# Generated by FakeRAM 2.0
VERSION 5.7 ;
BUSBITCHARS "[]" ;
PROPERTYDEFINITIONS
  MACRO width INTEGER ;
  MACRO depth INTEGER ;
  MACRO banks INTEGER ;
END PROPERTYDEFINITIONS
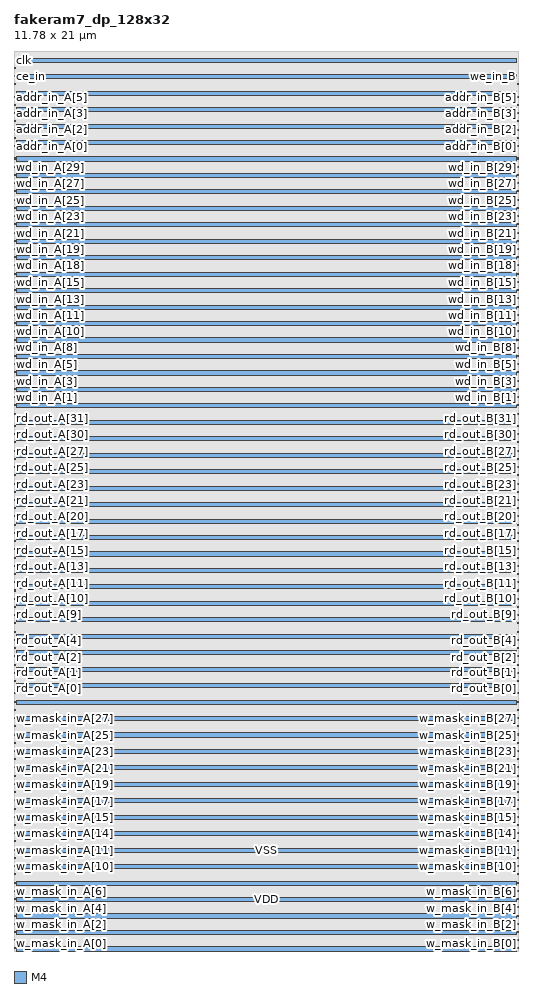
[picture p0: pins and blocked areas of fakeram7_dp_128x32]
MACRO fakeram7_dp_128x32
  PROPERTY width 32 ;
  PROPERTY depth 128 ;
  PROPERTY banks 2 ;
  FOREIGN fakeram7_dp_128x32 0 0 ;
  SYMMETRY X Y ;
  SIZE 11.780 BY 21.000 ;
  CLASS BLOCK ;
  PIN w_mask_in_A[0]
    DIRECTION INPUT ;
    USE SIGNAL ;
    SHAPE ABUTMENT ;
    PORT
      LAYER M4 ;
      RECT 0.000 0.048 0.024 0.072 ;
    END
  END w_mask_in_A[0]
  PIN w_mask_in_B[0]
    DIRECTION INPUT ;
    USE SIGNAL ;
    SHAPE ABUTMENT ;
    PORT
      LAYER M4 ;
      RECT 11.756 0.048 11.780 0.072 ;
    END
  END w_mask_in_B[0]
  PIN w_mask_in_A[1]
    DIRECTION INPUT ;
    USE SIGNAL ;
    SHAPE ABUTMENT ;
    PORT
      LAYER M4 ;
      RECT 0.000 0.240 0.024 0.264 ;
    END
  END w_mask_in_A[1]
  PIN w_mask_in_B[1]
    DIRECTION INPUT ;
    USE SIGNAL ;
    SHAPE ABUTMENT ;
    PORT
      LAYER M4 ;
      RECT 11.756 0.240 11.780 0.264 ;
    END
  END w_mask_in_B[1]
  PIN w_mask_in_A[2]
    DIRECTION INPUT ;
    USE SIGNAL ;
    SHAPE ABUTMENT ;
    PORT
      LAYER M4 ;
      RECT 0.000 0.432 0.024 0.456 ;
    END
  END w_mask_in_A[2]
  PIN w_mask_in_B[2]
    DIRECTION INPUT ;
    USE SIGNAL ;
    SHAPE ABUTMENT ;
    PORT
      LAYER M4 ;
      RECT 11.756 0.432 11.780 0.456 ;
    END
  END w_mask_in_B[2]
  PIN w_mask_in_A[3]
    DIRECTION INPUT ;
    USE SIGNAL ;
    SHAPE ABUTMENT ;
    PORT
      LAYER M4 ;
      RECT 0.000 0.624 0.024 0.648 ;
    END
  END w_mask_in_A[3]
  PIN w_mask_in_B[3]
    DIRECTION INPUT ;
    USE SIGNAL ;
    SHAPE ABUTMENT ;
    PORT
      LAYER M4 ;
      RECT 11.756 0.624 11.780 0.648 ;
    END
  END w_mask_in_B[3]
  PIN w_mask_in_A[4]
    DIRECTION INPUT ;
    USE SIGNAL ;
    SHAPE ABUTMENT ;
    PORT
      LAYER M4 ;
      RECT 0.000 0.816 0.024 0.840 ;
    END
  END w_mask_in_A[4]
  PIN w_mask_in_B[4]
    DIRECTION INPUT ;
    USE SIGNAL ;
    SHAPE ABUTMENT ;
    PORT
      LAYER M4 ;
      RECT 11.756 0.816 11.780 0.840 ;
    END
  END w_mask_in_B[4]
  PIN w_mask_in_A[5]
    DIRECTION INPUT ;
    USE SIGNAL ;
    SHAPE ABUTMENT ;
    PORT
      LAYER M4 ;
      RECT 0.000 1.008 0.024 1.032 ;
    END
  END w_mask_in_A[5]
  PIN w_mask_in_B[5]
    DIRECTION INPUT ;
    USE SIGNAL ;
    SHAPE ABUTMENT ;
    PORT
      LAYER M4 ;
      RECT 11.756 1.008 11.780 1.032 ;
    END
  END w_mask_in_B[5]
  PIN w_mask_in_A[6]
    DIRECTION INPUT ;
    USE SIGNAL ;
    SHAPE ABUTMENT ;
    PORT
      LAYER M4 ;
      RECT 0.000 1.200 0.024 1.224 ;
    END
  END w_mask_in_A[6]
  PIN w_mask_in_B[6]
    DIRECTION INPUT ;
    USE SIGNAL ;
    SHAPE ABUTMENT ;
    PORT
      LAYER M4 ;
      RECT 11.756 1.200 11.780 1.224 ;
    END
  END w_mask_in_B[6]
  PIN w_mask_in_A[7]
    DIRECTION INPUT ;
    USE SIGNAL ;
    SHAPE ABUTMENT ;
    PORT
      LAYER M4 ;
      RECT 0.000 1.392 0.024 1.416 ;
    END
  END w_mask_in_A[7]
  PIN w_mask_in_B[7]
    DIRECTION INPUT ;
    USE SIGNAL ;
    SHAPE ABUTMENT ;
    PORT
      LAYER M4 ;
      RECT 11.756 1.392 11.780 1.416 ;
    END
  END w_mask_in_B[7]
  PIN w_mask_in_A[8]
    DIRECTION INPUT ;
    USE SIGNAL ;
    SHAPE ABUTMENT ;
    PORT
      LAYER M4 ;
      RECT 0.000 1.584 0.024 1.608 ;
    END
  END w_mask_in_A[8]
  PIN w_mask_in_B[8]
    DIRECTION INPUT ;
    USE SIGNAL ;
    SHAPE ABUTMENT ;
    PORT
      LAYER M4 ;
      RECT 11.756 1.584 11.780 1.608 ;
    END
  END w_mask_in_B[8]
  PIN w_mask_in_A[9]
    DIRECTION INPUT ;
    USE SIGNAL ;
    SHAPE ABUTMENT ;
    PORT
      LAYER M4 ;
      RECT 0.000 1.776 0.024 1.800 ;
    END
  END w_mask_in_A[9]
  PIN w_mask_in_B[9]
    DIRECTION INPUT ;
    USE SIGNAL ;
    SHAPE ABUTMENT ;
    PORT
      LAYER M4 ;
      RECT 11.756 1.776 11.780 1.800 ;
    END
  END w_mask_in_B[9]
  PIN w_mask_in_A[10]
    DIRECTION INPUT ;
    USE SIGNAL ;
    SHAPE ABUTMENT ;
    PORT
      LAYER M4 ;
      RECT 0.000 1.968 0.024 1.992 ;
    END
  END w_mask_in_A[10]
  PIN w_mask_in_B[10]
    DIRECTION INPUT ;
    USE SIGNAL ;
    SHAPE ABUTMENT ;
    PORT
      LAYER M4 ;
      RECT 11.756 1.968 11.780 1.992 ;
    END
  END w_mask_in_B[10]
  PIN w_mask_in_A[11]
    DIRECTION INPUT ;
    USE SIGNAL ;
    SHAPE ABUTMENT ;
    PORT
      LAYER M4 ;
      RECT 0.000 2.160 0.024 2.184 ;
    END
  END w_mask_in_A[11]
  PIN w_mask_in_B[11]
    DIRECTION INPUT ;
    USE SIGNAL ;
    SHAPE ABUTMENT ;
    PORT
      LAYER M4 ;
      RECT 11.756 2.160 11.780 2.184 ;
    END
  END w_mask_in_B[11]
  PIN w_mask_in_A[12]
    DIRECTION INPUT ;
    USE SIGNAL ;
    SHAPE ABUTMENT ;
    PORT
      LAYER M4 ;
      RECT 0.000 2.352 0.024 2.376 ;
    END
  END w_mask_in_A[12]
  PIN w_mask_in_B[12]
    DIRECTION INPUT ;
    USE SIGNAL ;
    SHAPE ABUTMENT ;
    PORT
      LAYER M4 ;
      RECT 11.756 2.352 11.780 2.376 ;
    END
  END w_mask_in_B[12]
  PIN w_mask_in_A[13]
    DIRECTION INPUT ;
    USE SIGNAL ;
    SHAPE ABUTMENT ;
    PORT
      LAYER M4 ;
      RECT 0.000 2.544 0.024 2.568 ;
    END
  END w_mask_in_A[13]
  PIN w_mask_in_B[13]
    DIRECTION INPUT ;
    USE SIGNAL ;
    SHAPE ABUTMENT ;
    PORT
      LAYER M4 ;
      RECT 11.756 2.544 11.780 2.568 ;
    END
  END w_mask_in_B[13]
  PIN w_mask_in_A[14]
    DIRECTION INPUT ;
    USE SIGNAL ;
    SHAPE ABUTMENT ;
    PORT
      LAYER M4 ;
      RECT 0.000 2.736 0.024 2.760 ;
    END
  END w_mask_in_A[14]
  PIN w_mask_in_B[14]
    DIRECTION INPUT ;
    USE SIGNAL ;
    SHAPE ABUTMENT ;
    PORT
      LAYER M4 ;
      RECT 11.756 2.736 11.780 2.760 ;
    END
  END w_mask_in_B[14]
  PIN w_mask_in_A[15]
    DIRECTION INPUT ;
    USE SIGNAL ;
    SHAPE ABUTMENT ;
    PORT
      LAYER M4 ;
      RECT 0.000 2.928 0.024 2.952 ;
    END
  END w_mask_in_A[15]
  PIN w_mask_in_B[15]
    DIRECTION INPUT ;
    USE SIGNAL ;
    SHAPE ABUTMENT ;
    PORT
      LAYER M4 ;
      RECT 11.756 2.928 11.780 2.952 ;
    END
  END w_mask_in_B[15]
  PIN w_mask_in_A[16]
    DIRECTION INPUT ;
    USE SIGNAL ;
    SHAPE ABUTMENT ;
    PORT
      LAYER M4 ;
      RECT 0.000 3.120 0.024 3.144 ;
    END
  END w_mask_in_A[16]
  PIN w_mask_in_B[16]
    DIRECTION INPUT ;
    USE SIGNAL ;
    SHAPE ABUTMENT ;
    PORT
      LAYER M4 ;
      RECT 11.756 3.120 11.780 3.144 ;
    END
  END w_mask_in_B[16]
  PIN w_mask_in_A[17]
    DIRECTION INPUT ;
    USE SIGNAL ;
    SHAPE ABUTMENT ;
    PORT
      LAYER M4 ;
      RECT 0.000 3.312 0.024 3.336 ;
    END
  END w_mask_in_A[17]
  PIN w_mask_in_B[17]
    DIRECTION INPUT ;
    USE SIGNAL ;
    SHAPE ABUTMENT ;
    PORT
      LAYER M4 ;
      RECT 11.756 3.312 11.780 3.336 ;
    END
  END w_mask_in_B[17]
  PIN w_mask_in_A[18]
    DIRECTION INPUT ;
    USE SIGNAL ;
    SHAPE ABUTMENT ;
    PORT
      LAYER M4 ;
      RECT 0.000 3.504 0.024 3.528 ;
    END
  END w_mask_in_A[18]
  PIN w_mask_in_B[18]
    DIRECTION INPUT ;
    USE SIGNAL ;
    SHAPE ABUTMENT ;
    PORT
      LAYER M4 ;
      RECT 11.756 3.504 11.780 3.528 ;
    END
  END w_mask_in_B[18]
  PIN w_mask_in_A[19]
    DIRECTION INPUT ;
    USE SIGNAL ;
    SHAPE ABUTMENT ;
    PORT
      LAYER M4 ;
      RECT 0.000 3.696 0.024 3.720 ;
    END
  END w_mask_in_A[19]
  PIN w_mask_in_B[19]
    DIRECTION INPUT ;
    USE SIGNAL ;
    SHAPE ABUTMENT ;
    PORT
      LAYER M4 ;
      RECT 11.756 3.696 11.780 3.720 ;
    END
  END w_mask_in_B[19]
  PIN w_mask_in_A[20]
    DIRECTION INPUT ;
    USE SIGNAL ;
    SHAPE ABUTMENT ;
    PORT
      LAYER M4 ;
      RECT 0.000 3.888 0.024 3.912 ;
    END
  END w_mask_in_A[20]
  PIN w_mask_in_B[20]
    DIRECTION INPUT ;
    USE SIGNAL ;
    SHAPE ABUTMENT ;
    PORT
      LAYER M4 ;
      RECT 11.756 3.888 11.780 3.912 ;
    END
  END w_mask_in_B[20]
  PIN w_mask_in_A[21]
    DIRECTION INPUT ;
    USE SIGNAL ;
    SHAPE ABUTMENT ;
    PORT
      LAYER M4 ;
      RECT 0.000 4.080 0.024 4.104 ;
    END
  END w_mask_in_A[21]
  PIN w_mask_in_B[21]
    DIRECTION INPUT ;
    USE SIGNAL ;
    SHAPE ABUTMENT ;
    PORT
      LAYER M4 ;
      RECT 11.756 4.080 11.780 4.104 ;
    END
  END w_mask_in_B[21]
  PIN w_mask_in_A[22]
    DIRECTION INPUT ;
    USE SIGNAL ;
    SHAPE ABUTMENT ;
    PORT
      LAYER M4 ;
      RECT 0.000 4.272 0.024 4.296 ;
    END
  END w_mask_in_A[22]
  PIN w_mask_in_B[22]
    DIRECTION INPUT ;
    USE SIGNAL ;
    SHAPE ABUTMENT ;
    PORT
      LAYER M4 ;
      RECT 11.756 4.272 11.780 4.296 ;
    END
  END w_mask_in_B[22]
  PIN w_mask_in_A[23]
    DIRECTION INPUT ;
    USE SIGNAL ;
    SHAPE ABUTMENT ;
    PORT
      LAYER M4 ;
      RECT 0.000 4.464 0.024 4.488 ;
    END
  END w_mask_in_A[23]
  PIN w_mask_in_B[23]
    DIRECTION INPUT ;
    USE SIGNAL ;
    SHAPE ABUTMENT ;
    PORT
      LAYER M4 ;
      RECT 11.756 4.464 11.780 4.488 ;
    END
  END w_mask_in_B[23]
  PIN w_mask_in_A[24]
    DIRECTION INPUT ;
    USE SIGNAL ;
    SHAPE ABUTMENT ;
    PORT
      LAYER M4 ;
      RECT 0.000 4.656 0.024 4.680 ;
    END
  END w_mask_in_A[24]
  PIN w_mask_in_B[24]
    DIRECTION INPUT ;
    USE SIGNAL ;
    SHAPE ABUTMENT ;
    PORT
      LAYER M4 ;
      RECT 11.756 4.656 11.780 4.680 ;
    END
  END w_mask_in_B[24]
  PIN w_mask_in_A[25]
    DIRECTION INPUT ;
    USE SIGNAL ;
    SHAPE ABUTMENT ;
    PORT
      LAYER M4 ;
      RECT 0.000 4.848 0.024 4.872 ;
    END
  END w_mask_in_A[25]
  PIN w_mask_in_B[25]
    DIRECTION INPUT ;
    USE SIGNAL ;
    SHAPE ABUTMENT ;
    PORT
      LAYER M4 ;
      RECT 11.756 4.848 11.780 4.872 ;
    END
  END w_mask_in_B[25]
  PIN w_mask_in_A[26]
    DIRECTION INPUT ;
    USE SIGNAL ;
    SHAPE ABUTMENT ;
    PORT
      LAYER M4 ;
      RECT 0.000 5.040 0.024 5.064 ;
    END
  END w_mask_in_A[26]
  PIN w_mask_in_B[26]
    DIRECTION INPUT ;
    USE SIGNAL ;
    SHAPE ABUTMENT ;
    PORT
      LAYER M4 ;
      RECT 11.756 5.040 11.780 5.064 ;
    END
  END w_mask_in_B[26]
  PIN w_mask_in_A[27]
    DIRECTION INPUT ;
    USE SIGNAL ;
    SHAPE ABUTMENT ;
    PORT
      LAYER M4 ;
      RECT 0.000 5.232 0.024 5.256 ;
    END
  END w_mask_in_A[27]
  PIN w_mask_in_B[27]
    DIRECTION INPUT ;
    USE SIGNAL ;
    SHAPE ABUTMENT ;
    PORT
      LAYER M4 ;
      RECT 11.756 5.232 11.780 5.256 ;
    END
  END w_mask_in_B[27]
  PIN w_mask_in_A[28]
    DIRECTION INPUT ;
    USE SIGNAL ;
    SHAPE ABUTMENT ;
    PORT
      LAYER M4 ;
      RECT 0.000 5.424 0.024 5.448 ;
    END
  END w_mask_in_A[28]
  PIN w_mask_in_B[28]
    DIRECTION INPUT ;
    USE SIGNAL ;
    SHAPE ABUTMENT ;
    PORT
      LAYER M4 ;
      RECT 11.756 5.424 11.780 5.448 ;
    END
  END w_mask_in_B[28]
  PIN w_mask_in_A[29]
    DIRECTION INPUT ;
    USE SIGNAL ;
    SHAPE ABUTMENT ;
    PORT
      LAYER M4 ;
      RECT 0.000 5.616 0.024 5.640 ;
    END
  END w_mask_in_A[29]
  PIN w_mask_in_B[29]
    DIRECTION INPUT ;
    USE SIGNAL ;
    SHAPE ABUTMENT ;
    PORT
      LAYER M4 ;
      RECT 11.756 5.616 11.780 5.640 ;
    END
  END w_mask_in_B[29]
  PIN w_mask_in_A[30]
    DIRECTION INPUT ;
    USE SIGNAL ;
    SHAPE ABUTMENT ;
    PORT
      LAYER M4 ;
      RECT 0.000 5.808 0.024 5.832 ;
    END
  END w_mask_in_A[30]
  PIN w_mask_in_B[30]
    DIRECTION INPUT ;
    USE SIGNAL ;
    SHAPE ABUTMENT ;
    PORT
      LAYER M4 ;
      RECT 11.756 5.808 11.780 5.832 ;
    END
  END w_mask_in_B[30]
  PIN w_mask_in_A[31]
    DIRECTION INPUT ;
    USE SIGNAL ;
    SHAPE ABUTMENT ;
    PORT
      LAYER M4 ;
      RECT 0.000 6.000 0.024 6.024 ;
    END
  END w_mask_in_A[31]
  PIN w_mask_in_B[31]
    DIRECTION INPUT ;
    USE SIGNAL ;
    SHAPE ABUTMENT ;
    PORT
      LAYER M4 ;
      RECT 11.756 6.000 11.780 6.024 ;
    END
  END w_mask_in_B[31]
  PIN rd_out_A[0]
    DIRECTION OUTPUT ;
    USE SIGNAL ;
    SHAPE ABUTMENT ;
    PORT
      LAYER M4 ;
      RECT 0.000 6.288 0.024 6.312 ;
    END
  END rd_out_A[0]
  PIN rd_out_B[0]
    DIRECTION OUTPUT ;
    USE SIGNAL ;
    SHAPE ABUTMENT ;
    PORT
      LAYER M4 ;
      RECT 11.756 6.288 11.780 6.312 ;
    END
  END rd_out_B[0]
  PIN rd_out_A[1]
    DIRECTION OUTPUT ;
    USE SIGNAL ;
    SHAPE ABUTMENT ;
    PORT
      LAYER M4 ;
      RECT 0.000 6.480 0.024 6.504 ;
    END
  END rd_out_A[1]
  PIN rd_out_B[1]
    DIRECTION OUTPUT ;
    USE SIGNAL ;
    SHAPE ABUTMENT ;
    PORT
      LAYER M4 ;
      RECT 11.756 6.480 11.780 6.504 ;
    END
  END rd_out_B[1]
  PIN rd_out_A[2]
    DIRECTION OUTPUT ;
    USE SIGNAL ;
    SHAPE ABUTMENT ;
    PORT
      LAYER M4 ;
      RECT 0.000 6.672 0.024 6.696 ;
    END
  END rd_out_A[2]
  PIN rd_out_B[2]
    DIRECTION OUTPUT ;
    USE SIGNAL ;
    SHAPE ABUTMENT ;
    PORT
      LAYER M4 ;
      RECT 11.756 6.672 11.780 6.696 ;
    END
  END rd_out_B[2]
  PIN rd_out_A[3]
    DIRECTION OUTPUT ;
    USE SIGNAL ;
    SHAPE ABUTMENT ;
    PORT
      LAYER M4 ;
      RECT 0.000 6.864 0.024 6.888 ;
    END
  END rd_out_A[3]
  PIN rd_out_B[3]
    DIRECTION OUTPUT ;
    USE SIGNAL ;
    SHAPE ABUTMENT ;
    PORT
      LAYER M4 ;
      RECT 11.756 6.864 11.780 6.888 ;
    END
  END rd_out_B[3]
  PIN rd_out_A[4]
    DIRECTION OUTPUT ;
    USE SIGNAL ;
    SHAPE ABUTMENT ;
    PORT
      LAYER M4 ;
      RECT 0.000 7.056 0.024 7.080 ;
    END
  END rd_out_A[4]
  PIN rd_out_B[4]
    DIRECTION OUTPUT ;
    USE SIGNAL ;
    SHAPE ABUTMENT ;
    PORT
      LAYER M4 ;
      RECT 11.756 7.056 11.780 7.080 ;
    END
  END rd_out_B[4]
  PIN rd_out_A[5]
    DIRECTION OUTPUT ;
    USE SIGNAL ;
    SHAPE ABUTMENT ;
    PORT
      LAYER M4 ;
      RECT 0.000 7.248 0.024 7.272 ;
    END
  END rd_out_A[5]
  PIN rd_out_B[5]
    DIRECTION OUTPUT ;
    USE SIGNAL ;
    SHAPE ABUTMENT ;
    PORT
      LAYER M4 ;
      RECT 11.756 7.248 11.780 7.272 ;
    END
  END rd_out_B[5]
  PIN rd_out_A[6]
    DIRECTION OUTPUT ;
    USE SIGNAL ;
    SHAPE ABUTMENT ;
    PORT
      LAYER M4 ;
      RECT 0.000 7.440 0.024 7.464 ;
    END
  END rd_out_A[6]
  PIN rd_out_B[6]
    DIRECTION OUTPUT ;
    USE SIGNAL ;
    SHAPE ABUTMENT ;
    PORT
      LAYER M4 ;
      RECT 11.756 7.440 11.780 7.464 ;
    END
  END rd_out_B[6]
  PIN rd_out_A[7]
    DIRECTION OUTPUT ;
    USE SIGNAL ;
    SHAPE ABUTMENT ;
    PORT
      LAYER M4 ;
      RECT 0.000 7.632 0.024 7.656 ;
    END
  END rd_out_A[7]
  PIN rd_out_B[7]
    DIRECTION OUTPUT ;
    USE SIGNAL ;
    SHAPE ABUTMENT ;
    PORT
      LAYER M4 ;
      RECT 11.756 7.632 11.780 7.656 ;
    END
  END rd_out_B[7]
  PIN rd_out_A[8]
    DIRECTION OUTPUT ;
    USE SIGNAL ;
    SHAPE ABUTMENT ;
    PORT
      LAYER M4 ;
      RECT 0.000 7.824 0.024 7.848 ;
    END
  END rd_out_A[8]
  PIN rd_out_B[8]
    DIRECTION OUTPUT ;
    USE SIGNAL ;
    SHAPE ABUTMENT ;
    PORT
      LAYER M4 ;
      RECT 11.756 7.824 11.780 7.848 ;
    END
  END rd_out_B[8]
  PIN rd_out_A[9]
    DIRECTION OUTPUT ;
    USE SIGNAL ;
    SHAPE ABUTMENT ;
    PORT
      LAYER M4 ;
      RECT 0.000 8.016 0.024 8.040 ;
    END
  END rd_out_A[9]
  PIN rd_out_B[9]
    DIRECTION OUTPUT ;
    USE SIGNAL ;
    SHAPE ABUTMENT ;
    PORT
      LAYER M4 ;
      RECT 11.756 8.016 11.780 8.040 ;
    END
  END rd_out_B[9]
  PIN rd_out_A[10]
    DIRECTION OUTPUT ;
    USE SIGNAL ;
    SHAPE ABUTMENT ;
    PORT
      LAYER M4 ;
      RECT 0.000 8.208 0.024 8.232 ;
    END
  END rd_out_A[10]
  PIN rd_out_B[10]
    DIRECTION OUTPUT ;
    USE SIGNAL ;
    SHAPE ABUTMENT ;
    PORT
      LAYER M4 ;
      RECT 11.756 8.208 11.780 8.232 ;
    END
  END rd_out_B[10]
  PIN rd_out_A[11]
    DIRECTION OUTPUT ;
    USE SIGNAL ;
    SHAPE ABUTMENT ;
    PORT
      LAYER M4 ;
      RECT 0.000 8.400 0.024 8.424 ;
    END
  END rd_out_A[11]
  PIN rd_out_B[11]
    DIRECTION OUTPUT ;
    USE SIGNAL ;
    SHAPE ABUTMENT ;
    PORT
      LAYER M4 ;
      RECT 11.756 8.400 11.780 8.424 ;
    END
  END rd_out_B[11]
  PIN rd_out_A[12]
    DIRECTION OUTPUT ;
    USE SIGNAL ;
    SHAPE ABUTMENT ;
    PORT
      LAYER M4 ;
      RECT 0.000 8.592 0.024 8.616 ;
    END
  END rd_out_A[12]
  PIN rd_out_B[12]
    DIRECTION OUTPUT ;
    USE SIGNAL ;
    SHAPE ABUTMENT ;
    PORT
      LAYER M4 ;
      RECT 11.756 8.592 11.780 8.616 ;
    END
  END rd_out_B[12]
  PIN rd_out_A[13]
    DIRECTION OUTPUT ;
    USE SIGNAL ;
    SHAPE ABUTMENT ;
    PORT
      LAYER M4 ;
      RECT 0.000 8.784 0.024 8.808 ;
    END
  END rd_out_A[13]
  PIN rd_out_B[13]
    DIRECTION OUTPUT ;
    USE SIGNAL ;
    SHAPE ABUTMENT ;
    PORT
      LAYER M4 ;
      RECT 11.756 8.784 11.780 8.808 ;
    END
  END rd_out_B[13]
  PIN rd_out_A[14]
    DIRECTION OUTPUT ;
    USE SIGNAL ;
    SHAPE ABUTMENT ;
    PORT
      LAYER M4 ;
      RECT 0.000 8.976 0.024 9.000 ;
    END
  END rd_out_A[14]
  PIN rd_out_B[14]
    DIRECTION OUTPUT ;
    USE SIGNAL ;
    SHAPE ABUTMENT ;
    PORT
      LAYER M4 ;
      RECT 11.756 8.976 11.780 9.000 ;
    END
  END rd_out_B[14]
  PIN rd_out_A[15]
    DIRECTION OUTPUT ;
    USE SIGNAL ;
    SHAPE ABUTMENT ;
    PORT
      LAYER M4 ;
      RECT 0.000 9.168 0.024 9.192 ;
    END
  END rd_out_A[15]
  PIN rd_out_B[15]
    DIRECTION OUTPUT ;
    USE SIGNAL ;
    SHAPE ABUTMENT ;
    PORT
      LAYER M4 ;
      RECT 11.756 9.168 11.780 9.192 ;
    END
  END rd_out_B[15]
  PIN rd_out_A[16]
    DIRECTION OUTPUT ;
    USE SIGNAL ;
    SHAPE ABUTMENT ;
    PORT
      LAYER M4 ;
      RECT 0.000 9.360 0.024 9.384 ;
    END
  END rd_out_A[16]
  PIN rd_out_B[16]
    DIRECTION OUTPUT ;
    USE SIGNAL ;
    SHAPE ABUTMENT ;
    PORT
      LAYER M4 ;
      RECT 11.756 9.360 11.780 9.384 ;
    END
  END rd_out_B[16]
  PIN rd_out_A[17]
    DIRECTION OUTPUT ;
    USE SIGNAL ;
    SHAPE ABUTMENT ;
    PORT
      LAYER M4 ;
      RECT 0.000 9.552 0.024 9.576 ;
    END
  END rd_out_A[17]
  PIN rd_out_B[17]
    DIRECTION OUTPUT ;
    USE SIGNAL ;
    SHAPE ABUTMENT ;
    PORT
      LAYER M4 ;
      RECT 11.756 9.552 11.780 9.576 ;
    END
  END rd_out_B[17]
  PIN rd_out_A[18]
    DIRECTION OUTPUT ;
    USE SIGNAL ;
    SHAPE ABUTMENT ;
    PORT
      LAYER M4 ;
      RECT 0.000 9.744 0.024 9.768 ;
    END
  END rd_out_A[18]
  PIN rd_out_B[18]
    DIRECTION OUTPUT ;
    USE SIGNAL ;
    SHAPE ABUTMENT ;
    PORT
      LAYER M4 ;
      RECT 11.756 9.744 11.780 9.768 ;
    END
  END rd_out_B[18]
  PIN rd_out_A[19]
    DIRECTION OUTPUT ;
    USE SIGNAL ;
    SHAPE ABUTMENT ;
    PORT
      LAYER M4 ;
      RECT 0.000 9.936 0.024 9.960 ;
    END
  END rd_out_A[19]
  PIN rd_out_B[19]
    DIRECTION OUTPUT ;
    USE SIGNAL ;
    SHAPE ABUTMENT ;
    PORT
      LAYER M4 ;
      RECT 11.756 9.936 11.780 9.960 ;
    END
  END rd_out_B[19]
  PIN rd_out_A[20]
    DIRECTION OUTPUT ;
    USE SIGNAL ;
    SHAPE ABUTMENT ;
    PORT
      LAYER M4 ;
      RECT 0.000 10.128 0.024 10.152 ;
    END
  END rd_out_A[20]
  PIN rd_out_B[20]
    DIRECTION OUTPUT ;
    USE SIGNAL ;
    SHAPE ABUTMENT ;
    PORT
      LAYER M4 ;
      RECT 11.756 10.128 11.780 10.152 ;
    END
  END rd_out_B[20]
  PIN rd_out_A[21]
    DIRECTION OUTPUT ;
    USE SIGNAL ;
    SHAPE ABUTMENT ;
    PORT
      LAYER M4 ;
      RECT 0.000 10.320 0.024 10.344 ;
    END
  END rd_out_A[21]
  PIN rd_out_B[21]
    DIRECTION OUTPUT ;
    USE SIGNAL ;
    SHAPE ABUTMENT ;
    PORT
      LAYER M4 ;
      RECT 11.756 10.320 11.780 10.344 ;
    END
  END rd_out_B[21]
  PIN rd_out_A[22]
    DIRECTION OUTPUT ;
    USE SIGNAL ;
    SHAPE ABUTMENT ;
    PORT
      LAYER M4 ;
      RECT 0.000 10.512 0.024 10.536 ;
    END
  END rd_out_A[22]
  PIN rd_out_B[22]
    DIRECTION OUTPUT ;
    USE SIGNAL ;
    SHAPE ABUTMENT ;
    PORT
      LAYER M4 ;
      RECT 11.756 10.512 11.780 10.536 ;
    END
  END rd_out_B[22]
  PIN rd_out_A[23]
    DIRECTION OUTPUT ;
    USE SIGNAL ;
    SHAPE ABUTMENT ;
    PORT
      LAYER M4 ;
      RECT 0.000 10.704 0.024 10.728 ;
    END
  END rd_out_A[23]
  PIN rd_out_B[23]
    DIRECTION OUTPUT ;
    USE SIGNAL ;
    SHAPE ABUTMENT ;
    PORT
      LAYER M4 ;
      RECT 11.756 10.704 11.780 10.728 ;
    END
  END rd_out_B[23]
  PIN rd_out_A[24]
    DIRECTION OUTPUT ;
    USE SIGNAL ;
    SHAPE ABUTMENT ;
    PORT
      LAYER M4 ;
      RECT 0.000 10.896 0.024 10.920 ;
    END
  END rd_out_A[24]
  PIN rd_out_B[24]
    DIRECTION OUTPUT ;
    USE SIGNAL ;
    SHAPE ABUTMENT ;
    PORT
      LAYER M4 ;
      RECT 11.756 10.896 11.780 10.920 ;
    END
  END rd_out_B[24]
  PIN rd_out_A[25]
    DIRECTION OUTPUT ;
    USE SIGNAL ;
    SHAPE ABUTMENT ;
    PORT
      LAYER M4 ;
      RECT 0.000 11.088 0.024 11.112 ;
    END
  END rd_out_A[25]
  PIN rd_out_B[25]
    DIRECTION OUTPUT ;
    USE SIGNAL ;
    SHAPE ABUTMENT ;
    PORT
      LAYER M4 ;
      RECT 11.756 11.088 11.780 11.112 ;
    END
  END rd_out_B[25]
  PIN rd_out_A[26]
    DIRECTION OUTPUT ;
    USE SIGNAL ;
    SHAPE ABUTMENT ;
    PORT
      LAYER M4 ;
      RECT 0.000 11.280 0.024 11.304 ;
    END
  END rd_out_A[26]
  PIN rd_out_B[26]
    DIRECTION OUTPUT ;
    USE SIGNAL ;
    SHAPE ABUTMENT ;
    PORT
      LAYER M4 ;
      RECT 11.756 11.280 11.780 11.304 ;
    END
  END rd_out_B[26]
  PIN rd_out_A[27]
    DIRECTION OUTPUT ;
    USE SIGNAL ;
    SHAPE ABUTMENT ;
    PORT
      LAYER M4 ;
      RECT 0.000 11.472 0.024 11.496 ;
    END
  END rd_out_A[27]
  PIN rd_out_B[27]
    DIRECTION OUTPUT ;
    USE SIGNAL ;
    SHAPE ABUTMENT ;
    PORT
      LAYER M4 ;
      RECT 11.756 11.472 11.780 11.496 ;
    END
  END rd_out_B[27]
  PIN rd_out_A[28]
    DIRECTION OUTPUT ;
    USE SIGNAL ;
    SHAPE ABUTMENT ;
    PORT
      LAYER M4 ;
      RECT 0.000 11.664 0.024 11.688 ;
    END
  END rd_out_A[28]
  PIN rd_out_B[28]
    DIRECTION OUTPUT ;
    USE SIGNAL ;
    SHAPE ABUTMENT ;
    PORT
      LAYER M4 ;
      RECT 11.756 11.664 11.780 11.688 ;
    END
  END rd_out_B[28]
  PIN rd_out_A[29]
    DIRECTION OUTPUT ;
    USE SIGNAL ;
    SHAPE ABUTMENT ;
    PORT
      LAYER M4 ;
      RECT 0.000 11.856 0.024 11.880 ;
    END
  END rd_out_A[29]
  PIN rd_out_B[29]
    DIRECTION OUTPUT ;
    USE SIGNAL ;
    SHAPE ABUTMENT ;
    PORT
      LAYER M4 ;
      RECT 11.756 11.856 11.780 11.880 ;
    END
  END rd_out_B[29]
  PIN rd_out_A[30]
    DIRECTION OUTPUT ;
    USE SIGNAL ;
    SHAPE ABUTMENT ;
    PORT
      LAYER M4 ;
      RECT 0.000 12.048 0.024 12.072 ;
    END
  END rd_out_A[30]
  PIN rd_out_B[30]
    DIRECTION OUTPUT ;
    USE SIGNAL ;
    SHAPE ABUTMENT ;
    PORT
      LAYER M4 ;
      RECT 11.756 12.048 11.780 12.072 ;
    END
  END rd_out_B[30]
  PIN rd_out_A[31]
    DIRECTION OUTPUT ;
    USE SIGNAL ;
    SHAPE ABUTMENT ;
    PORT
      LAYER M4 ;
      RECT 0.000 12.240 0.024 12.264 ;
    END
  END rd_out_A[31]
  PIN rd_out_B[31]
    DIRECTION OUTPUT ;
    USE SIGNAL ;
    SHAPE ABUTMENT ;
    PORT
      LAYER M4 ;
      RECT 11.756 12.240 11.780 12.264 ;
    END
  END rd_out_B[31]
  PIN wd_in_A[0]
    DIRECTION INPUT ;
    USE SIGNAL ;
    SHAPE ABUTMENT ;
    PORT
      LAYER M4 ;
      RECT 0.000 12.528 0.024 12.552 ;
    END
  END wd_in_A[0]
  PIN wd_in_B[0]
    DIRECTION INPUT ;
    USE SIGNAL ;
    SHAPE ABUTMENT ;
    PORT
      LAYER M4 ;
      RECT 11.756 12.528 11.780 12.552 ;
    END
  END wd_in_B[0]
  PIN wd_in_A[1]
    DIRECTION INPUT ;
    USE SIGNAL ;
    SHAPE ABUTMENT ;
    PORT
      LAYER M4 ;
      RECT 0.000 12.720 0.024 12.744 ;
    END
  END wd_in_A[1]
  PIN wd_in_B[1]
    DIRECTION INPUT ;
    USE SIGNAL ;
    SHAPE ABUTMENT ;
    PORT
      LAYER M4 ;
      RECT 11.756 12.720 11.780 12.744 ;
    END
  END wd_in_B[1]
  PIN wd_in_A[2]
    DIRECTION INPUT ;
    USE SIGNAL ;
    SHAPE ABUTMENT ;
    PORT
      LAYER M4 ;
      RECT 0.000 12.912 0.024 12.936 ;
    END
  END wd_in_A[2]
  PIN wd_in_B[2]
    DIRECTION INPUT ;
    USE SIGNAL ;
    SHAPE ABUTMENT ;
    PORT
      LAYER M4 ;
      RECT 11.756 12.912 11.780 12.936 ;
    END
  END wd_in_B[2]
  PIN wd_in_A[3]
    DIRECTION INPUT ;
    USE SIGNAL ;
    SHAPE ABUTMENT ;
    PORT
      LAYER M4 ;
      RECT 0.000 13.104 0.024 13.128 ;
    END
  END wd_in_A[3]
  PIN wd_in_B[3]
    DIRECTION INPUT ;
    USE SIGNAL ;
    SHAPE ABUTMENT ;
    PORT
      LAYER M4 ;
      RECT 11.756 13.104 11.780 13.128 ;
    END
  END wd_in_B[3]
  PIN wd_in_A[4]
    DIRECTION INPUT ;
    USE SIGNAL ;
    SHAPE ABUTMENT ;
    PORT
      LAYER M4 ;
      RECT 0.000 13.296 0.024 13.320 ;
    END
  END wd_in_A[4]
  PIN wd_in_B[4]
    DIRECTION INPUT ;
    USE SIGNAL ;
    SHAPE ABUTMENT ;
    PORT
      LAYER M4 ;
      RECT 11.756 13.296 11.780 13.320 ;
    END
  END wd_in_B[4]
  PIN wd_in_A[5]
    DIRECTION INPUT ;
    USE SIGNAL ;
    SHAPE ABUTMENT ;
    PORT
      LAYER M4 ;
      RECT 0.000 13.488 0.024 13.512 ;
    END
  END wd_in_A[5]
  PIN wd_in_B[5]
    DIRECTION INPUT ;
    USE SIGNAL ;
    SHAPE ABUTMENT ;
    PORT
      LAYER M4 ;
      RECT 11.756 13.488 11.780 13.512 ;
    END
  END wd_in_B[5]
  PIN wd_in_A[6]
    DIRECTION INPUT ;
    USE SIGNAL ;
    SHAPE ABUTMENT ;
    PORT
      LAYER M4 ;
      RECT 0.000 13.680 0.024 13.704 ;
    END
  END wd_in_A[6]
  PIN wd_in_B[6]
    DIRECTION INPUT ;
    USE SIGNAL ;
    SHAPE ABUTMENT ;
    PORT
      LAYER M4 ;
      RECT 11.756 13.680 11.780 13.704 ;
    END
  END wd_in_B[6]
  PIN wd_in_A[7]
    DIRECTION INPUT ;
    USE SIGNAL ;
    SHAPE ABUTMENT ;
    PORT
      LAYER M4 ;
      RECT 0.000 13.872 0.024 13.896 ;
    END
  END wd_in_A[7]
  PIN wd_in_B[7]
    DIRECTION INPUT ;
    USE SIGNAL ;
    SHAPE ABUTMENT ;
    PORT
      LAYER M4 ;
      RECT 11.756 13.872 11.780 13.896 ;
    END
  END wd_in_B[7]
  PIN wd_in_A[8]
    DIRECTION INPUT ;
    USE SIGNAL ;
    SHAPE ABUTMENT ;
    PORT
      LAYER M4 ;
      RECT 0.000 14.064 0.024 14.088 ;
    END
  END wd_in_A[8]
  PIN wd_in_B[8]
    DIRECTION INPUT ;
    USE SIGNAL ;
    SHAPE ABUTMENT ;
    PORT
      LAYER M4 ;
      RECT 11.756 14.064 11.780 14.088 ;
    END
  END wd_in_B[8]
  PIN wd_in_A[9]
    DIRECTION INPUT ;
    USE SIGNAL ;
    SHAPE ABUTMENT ;
    PORT
      LAYER M4 ;
      RECT 0.000 14.256 0.024 14.280 ;
    END
  END wd_in_A[9]
  PIN wd_in_B[9]
    DIRECTION INPUT ;
    USE SIGNAL ;
    SHAPE ABUTMENT ;
    PORT
      LAYER M4 ;
      RECT 11.756 14.256 11.780 14.280 ;
    END
  END wd_in_B[9]
  PIN wd_in_A[10]
    DIRECTION INPUT ;
    USE SIGNAL ;
    SHAPE ABUTMENT ;
    PORT
      LAYER M4 ;
      RECT 0.000 14.448 0.024 14.472 ;
    END
  END wd_in_A[10]
  PIN wd_in_B[10]
    DIRECTION INPUT ;
    USE SIGNAL ;
    SHAPE ABUTMENT ;
    PORT
      LAYER M4 ;
      RECT 11.756 14.448 11.780 14.472 ;
    END
  END wd_in_B[10]
  PIN wd_in_A[11]
    DIRECTION INPUT ;
    USE SIGNAL ;
    SHAPE ABUTMENT ;
    PORT
      LAYER M4 ;
      RECT 0.000 14.640 0.024 14.664 ;
    END
  END wd_in_A[11]
  PIN wd_in_B[11]
    DIRECTION INPUT ;
    USE SIGNAL ;
    SHAPE ABUTMENT ;
    PORT
      LAYER M4 ;
      RECT 11.756 14.640 11.780 14.664 ;
    END
  END wd_in_B[11]
  PIN wd_in_A[12]
    DIRECTION INPUT ;
    USE SIGNAL ;
    SHAPE ABUTMENT ;
    PORT
      LAYER M4 ;
      RECT 0.000 14.832 0.024 14.856 ;
    END
  END wd_in_A[12]
  PIN wd_in_B[12]
    DIRECTION INPUT ;
    USE SIGNAL ;
    SHAPE ABUTMENT ;
    PORT
      LAYER M4 ;
      RECT 11.756 14.832 11.780 14.856 ;
    END
  END wd_in_B[12]
  PIN wd_in_A[13]
    DIRECTION INPUT ;
    USE SIGNAL ;
    SHAPE ABUTMENT ;
    PORT
      LAYER M4 ;
      RECT 0.000 15.024 0.024 15.048 ;
    END
  END wd_in_A[13]
  PIN wd_in_B[13]
    DIRECTION INPUT ;
    USE SIGNAL ;
    SHAPE ABUTMENT ;
    PORT
      LAYER M4 ;
      RECT 11.756 15.024 11.780 15.048 ;
    END
  END wd_in_B[13]
  PIN wd_in_A[14]
    DIRECTION INPUT ;
    USE SIGNAL ;
    SHAPE ABUTMENT ;
    PORT
      LAYER M4 ;
      RECT 0.000 15.216 0.024 15.240 ;
    END
  END wd_in_A[14]
  PIN wd_in_B[14]
    DIRECTION INPUT ;
    USE SIGNAL ;
    SHAPE ABUTMENT ;
    PORT
      LAYER M4 ;
      RECT 11.756 15.216 11.780 15.240 ;
    END
  END wd_in_B[14]
  PIN wd_in_A[15]
    DIRECTION INPUT ;
    USE SIGNAL ;
    SHAPE ABUTMENT ;
    PORT
      LAYER M4 ;
      RECT 0.000 15.408 0.024 15.432 ;
    END
  END wd_in_A[15]
  PIN wd_in_B[15]
    DIRECTION INPUT ;
    USE SIGNAL ;
    SHAPE ABUTMENT ;
    PORT
      LAYER M4 ;
      RECT 11.756 15.408 11.780 15.432 ;
    END
  END wd_in_B[15]
  PIN wd_in_A[16]
    DIRECTION INPUT ;
    USE SIGNAL ;
    SHAPE ABUTMENT ;
    PORT
      LAYER M4 ;
      RECT 0.000 15.600 0.024 15.624 ;
    END
  END wd_in_A[16]
  PIN wd_in_B[16]
    DIRECTION INPUT ;
    USE SIGNAL ;
    SHAPE ABUTMENT ;
    PORT
      LAYER M4 ;
      RECT 11.756 15.600 11.780 15.624 ;
    END
  END wd_in_B[16]
  PIN wd_in_A[17]
    DIRECTION INPUT ;
    USE SIGNAL ;
    SHAPE ABUTMENT ;
    PORT
      LAYER M4 ;
      RECT 0.000 15.792 0.024 15.816 ;
    END
  END wd_in_A[17]
  PIN wd_in_B[17]
    DIRECTION INPUT ;
    USE SIGNAL ;
    SHAPE ABUTMENT ;
    PORT
      LAYER M4 ;
      RECT 11.756 15.792 11.780 15.816 ;
    END
  END wd_in_B[17]
  PIN wd_in_A[18]
    DIRECTION INPUT ;
    USE SIGNAL ;
    SHAPE ABUTMENT ;
    PORT
      LAYER M4 ;
      RECT 0.000 15.984 0.024 16.008 ;
    END
  END wd_in_A[18]
  PIN wd_in_B[18]
    DIRECTION INPUT ;
    USE SIGNAL ;
    SHAPE ABUTMENT ;
    PORT
      LAYER M4 ;
      RECT 11.756 15.984 11.780 16.008 ;
    END
  END wd_in_B[18]
  PIN wd_in_A[19]
    DIRECTION INPUT ;
    USE SIGNAL ;
    SHAPE ABUTMENT ;
    PORT
      LAYER M4 ;
      RECT 0.000 16.176 0.024 16.200 ;
    END
  END wd_in_A[19]
  PIN wd_in_B[19]
    DIRECTION INPUT ;
    USE SIGNAL ;
    SHAPE ABUTMENT ;
    PORT
      LAYER M4 ;
      RECT 11.756 16.176 11.780 16.200 ;
    END
  END wd_in_B[19]
  PIN wd_in_A[20]
    DIRECTION INPUT ;
    USE SIGNAL ;
    SHAPE ABUTMENT ;
    PORT
      LAYER M4 ;
      RECT 0.000 16.368 0.024 16.392 ;
    END
  END wd_in_A[20]
  PIN wd_in_B[20]
    DIRECTION INPUT ;
    USE SIGNAL ;
    SHAPE ABUTMENT ;
    PORT
      LAYER M4 ;
      RECT 11.756 16.368 11.780 16.392 ;
    END
  END wd_in_B[20]
  PIN wd_in_A[21]
    DIRECTION INPUT ;
    USE SIGNAL ;
    SHAPE ABUTMENT ;
    PORT
      LAYER M4 ;
      RECT 0.000 16.560 0.024 16.584 ;
    END
  END wd_in_A[21]
  PIN wd_in_B[21]
    DIRECTION INPUT ;
    USE SIGNAL ;
    SHAPE ABUTMENT ;
    PORT
      LAYER M4 ;
      RECT 11.756 16.560 11.780 16.584 ;
    END
  END wd_in_B[21]
  PIN wd_in_A[22]
    DIRECTION INPUT ;
    USE SIGNAL ;
    SHAPE ABUTMENT ;
    PORT
      LAYER M4 ;
      RECT 0.000 16.752 0.024 16.776 ;
    END
  END wd_in_A[22]
  PIN wd_in_B[22]
    DIRECTION INPUT ;
    USE SIGNAL ;
    SHAPE ABUTMENT ;
    PORT
      LAYER M4 ;
      RECT 11.756 16.752 11.780 16.776 ;
    END
  END wd_in_B[22]
  PIN wd_in_A[23]
    DIRECTION INPUT ;
    USE SIGNAL ;
    SHAPE ABUTMENT ;
    PORT
      LAYER M4 ;
      RECT 0.000 16.944 0.024 16.968 ;
    END
  END wd_in_A[23]
  PIN wd_in_B[23]
    DIRECTION INPUT ;
    USE SIGNAL ;
    SHAPE ABUTMENT ;
    PORT
      LAYER M4 ;
      RECT 11.756 16.944 11.780 16.968 ;
    END
  END wd_in_B[23]
  PIN wd_in_A[24]
    DIRECTION INPUT ;
    USE SIGNAL ;
    SHAPE ABUTMENT ;
    PORT
      LAYER M4 ;
      RECT 0.000 17.136 0.024 17.160 ;
    END
  END wd_in_A[24]
  PIN wd_in_B[24]
    DIRECTION INPUT ;
    USE SIGNAL ;
    SHAPE ABUTMENT ;
    PORT
      LAYER M4 ;
      RECT 11.756 17.136 11.780 17.160 ;
    END
  END wd_in_B[24]
  PIN wd_in_A[25]
    DIRECTION INPUT ;
    USE SIGNAL ;
    SHAPE ABUTMENT ;
    PORT
      LAYER M4 ;
      RECT 0.000 17.328 0.024 17.352 ;
    END
  END wd_in_A[25]
  PIN wd_in_B[25]
    DIRECTION INPUT ;
    USE SIGNAL ;
    SHAPE ABUTMENT ;
    PORT
      LAYER M4 ;
      RECT 11.756 17.328 11.780 17.352 ;
    END
  END wd_in_B[25]
  PIN wd_in_A[26]
    DIRECTION INPUT ;
    USE SIGNAL ;
    SHAPE ABUTMENT ;
    PORT
      LAYER M4 ;
      RECT 0.000 17.520 0.024 17.544 ;
    END
  END wd_in_A[26]
  PIN wd_in_B[26]
    DIRECTION INPUT ;
    USE SIGNAL ;
    SHAPE ABUTMENT ;
    PORT
      LAYER M4 ;
      RECT 11.756 17.520 11.780 17.544 ;
    END
  END wd_in_B[26]
  PIN wd_in_A[27]
    DIRECTION INPUT ;
    USE SIGNAL ;
    SHAPE ABUTMENT ;
    PORT
      LAYER M4 ;
      RECT 0.000 17.712 0.024 17.736 ;
    END
  END wd_in_A[27]
  PIN wd_in_B[27]
    DIRECTION INPUT ;
    USE SIGNAL ;
    SHAPE ABUTMENT ;
    PORT
      LAYER M4 ;
      RECT 11.756 17.712 11.780 17.736 ;
    END
  END wd_in_B[27]
  PIN wd_in_A[28]
    DIRECTION INPUT ;
    USE SIGNAL ;
    SHAPE ABUTMENT ;
    PORT
      LAYER M4 ;
      RECT 0.000 17.904 0.024 17.928 ;
    END
  END wd_in_A[28]
  PIN wd_in_B[28]
    DIRECTION INPUT ;
    USE SIGNAL ;
    SHAPE ABUTMENT ;
    PORT
      LAYER M4 ;
      RECT 11.756 17.904 11.780 17.928 ;
    END
  END wd_in_B[28]
  PIN wd_in_A[29]
    DIRECTION INPUT ;
    USE SIGNAL ;
    SHAPE ABUTMENT ;
    PORT
      LAYER M4 ;
      RECT 0.000 18.096 0.024 18.120 ;
    END
  END wd_in_A[29]
  PIN wd_in_B[29]
    DIRECTION INPUT ;
    USE SIGNAL ;
    SHAPE ABUTMENT ;
    PORT
      LAYER M4 ;
      RECT 11.756 18.096 11.780 18.120 ;
    END
  END wd_in_B[29]
  PIN wd_in_A[30]
    DIRECTION INPUT ;
    USE SIGNAL ;
    SHAPE ABUTMENT ;
    PORT
      LAYER M4 ;
      RECT 0.000 18.288 0.024 18.312 ;
    END
  END wd_in_A[30]
  PIN wd_in_B[30]
    DIRECTION INPUT ;
    USE SIGNAL ;
    SHAPE ABUTMENT ;
    PORT
      LAYER M4 ;
      RECT 11.756 18.288 11.780 18.312 ;
    END
  END wd_in_B[30]
  PIN wd_in_A[31]
    DIRECTION INPUT ;
    USE SIGNAL ;
    SHAPE ABUTMENT ;
    PORT
      LAYER M4 ;
      RECT 0.000 18.480 0.024 18.504 ;
    END
  END wd_in_A[31]
  PIN wd_in_B[31]
    DIRECTION INPUT ;
    USE SIGNAL ;
    SHAPE ABUTMENT ;
    PORT
      LAYER M4 ;
      RECT 11.756 18.480 11.780 18.504 ;
    END
  END wd_in_B[31]
  PIN addr_in_A[0]
    DIRECTION INPUT ;
    USE SIGNAL ;
    SHAPE ABUTMENT ;
    PORT
      LAYER M4 ;
      RECT 0.000 18.768 0.024 18.792 ;
    END
  END addr_in_A[0]
  PIN addr_in_B[0]
    DIRECTION INPUT ;
    USE SIGNAL ;
    SHAPE ABUTMENT ;
    PORT
      LAYER M4 ;
      RECT 11.756 18.768 11.780 18.792 ;
    END
  END addr_in_B[0]
  PIN addr_in_A[1]
    DIRECTION INPUT ;
    USE SIGNAL ;
    SHAPE ABUTMENT ;
    PORT
      LAYER M4 ;
      RECT 0.000 18.960 0.024 18.984 ;
    END
  END addr_in_A[1]
  PIN addr_in_B[1]
    DIRECTION INPUT ;
    USE SIGNAL ;
    SHAPE ABUTMENT ;
    PORT
      LAYER M4 ;
      RECT 11.756 18.960 11.780 18.984 ;
    END
  END addr_in_B[1]
  PIN addr_in_A[2]
    DIRECTION INPUT ;
    USE SIGNAL ;
    SHAPE ABUTMENT ;
    PORT
      LAYER M4 ;
      RECT 0.000 19.152 0.024 19.176 ;
    END
  END addr_in_A[2]
  PIN addr_in_B[2]
    DIRECTION INPUT ;
    USE SIGNAL ;
    SHAPE ABUTMENT ;
    PORT
      LAYER M4 ;
      RECT 11.756 19.152 11.780 19.176 ;
    END
  END addr_in_B[2]
  PIN addr_in_A[3]
    DIRECTION INPUT ;
    USE SIGNAL ;
    SHAPE ABUTMENT ;
    PORT
      LAYER M4 ;
      RECT 0.000 19.344 0.024 19.368 ;
    END
  END addr_in_A[3]
  PIN addr_in_B[3]
    DIRECTION INPUT ;
    USE SIGNAL ;
    SHAPE ABUTMENT ;
    PORT
      LAYER M4 ;
      RECT 11.756 19.344 11.780 19.368 ;
    END
  END addr_in_B[3]
  PIN addr_in_A[4]
    DIRECTION INPUT ;
    USE SIGNAL ;
    SHAPE ABUTMENT ;
    PORT
      LAYER M4 ;
      RECT 0.000 19.536 0.024 19.560 ;
    END
  END addr_in_A[4]
  PIN addr_in_B[4]
    DIRECTION INPUT ;
    USE SIGNAL ;
    SHAPE ABUTMENT ;
    PORT
      LAYER M4 ;
      RECT 11.756 19.536 11.780 19.560 ;
    END
  END addr_in_B[4]
  PIN addr_in_A[5]
    DIRECTION INPUT ;
    USE SIGNAL ;
    SHAPE ABUTMENT ;
    PORT
      LAYER M4 ;
      RECT 0.000 19.728 0.024 19.752 ;
    END
  END addr_in_A[5]
  PIN addr_in_B[5]
    DIRECTION INPUT ;
    USE SIGNAL ;
    SHAPE ABUTMENT ;
    PORT
      LAYER M4 ;
      RECT 11.756 19.728 11.780 19.752 ;
    END
  END addr_in_B[5]
  PIN addr_in_A[6]
    DIRECTION INPUT ;
    USE SIGNAL ;
    SHAPE ABUTMENT ;
    PORT
      LAYER M4 ;
      RECT 0.000 19.920 0.024 19.944 ;
    END
  END addr_in_A[6]
  PIN addr_in_B[6]
    DIRECTION INPUT ;
    USE SIGNAL ;
    SHAPE ABUTMENT ;
    PORT
      LAYER M4 ;
      RECT 11.756 19.920 11.780 19.944 ;
    END
  END addr_in_B[6]
  PIN we_in_A
    DIRECTION INPUT ;
    USE SIGNAL ;
    SHAPE ABUTMENT ;
    PORT
      LAYER M4 ;
      RECT 0.000 20.208 0.024 20.232 ;
    END
  END we_in_A
  PIN we_in_B
    DIRECTION INPUT ;
    USE SIGNAL ;
    SHAPE ABUTMENT ;
    PORT
      LAYER M4 ;
      RECT 11.756 20.208 11.780 20.232 ;
    END
  END we_in_B
  PIN ce_in
    DIRECTION INPUT ;
    USE SIGNAL ;
    SHAPE ABUTMENT ;
    PORT
      LAYER M4 ;
      RECT 0.000 20.400 0.024 20.424 ;
    END
  END ce_in
  PIN clk
    DIRECTION INPUT ;
    USE SIGNAL ;
    SHAPE ABUTMENT ;
    PORT
      LAYER M4 ;
      RECT 0.000 20.592 0.024 20.616 ;
    END
  END clk
  PIN VSS
    DIRECTION INOUT ;
    USE GROUND ;
    PORT
      LAYER M4 ;
      RECT 0.048 0.000 11.732 0.096 ;
      RECT 0.048 0.768 11.732 0.864 ;
      RECT 0.048 1.536 11.732 1.632 ;
      RECT 0.048 2.304 11.732 2.400 ;
      RECT 0.048 3.072 11.732 3.168 ;
      RECT 0.048 3.840 11.732 3.936 ;
      RECT 0.048 4.608 11.732 4.704 ;
      RECT 0.048 5.376 11.732 5.472 ;
      RECT 0.048 6.144 11.732 6.240 ;
      RECT 0.048 6.912 11.732 7.008 ;
      RECT 0.048 7.680 11.732 7.776 ;
      RECT 0.048 8.448 11.732 8.544 ;
      RECT 0.048 9.216 11.732 9.312 ;
      RECT 0.048 9.984 11.732 10.080 ;
      RECT 0.048 10.752 11.732 10.848 ;
      RECT 0.048 11.520 11.732 11.616 ;
      RECT 0.048 12.288 11.732 12.384 ;
      RECT 0.048 13.056 11.732 13.152 ;
      RECT 0.048 13.824 11.732 13.920 ;
      RECT 0.048 14.592 11.732 14.688 ;
      RECT 0.048 15.360 11.732 15.456 ;
      RECT 0.048 16.128 11.732 16.224 ;
      RECT 0.048 16.896 11.732 16.992 ;
      RECT 0.048 17.664 11.732 17.760 ;
      RECT 0.048 18.432 11.732 18.528 ;
      RECT 0.048 19.200 11.732 19.296 ;
      RECT 0.048 19.968 11.732 20.064 ;
      RECT 0.048 20.736 11.732 20.832 ;
    END
  END VSS
  PIN VDD
    DIRECTION INOUT ;
    USE POWER ;
    PORT
      LAYER M4 ;
      RECT 0.048 0.384 11.732 0.480 ;
      RECT 0.048 1.152 11.732 1.248 ;
      RECT 0.048 1.920 11.732 2.016 ;
      RECT 0.048 2.688 11.732 2.784 ;
      RECT 0.048 3.456 11.732 3.552 ;
      RECT 0.048 4.224 11.732 4.320 ;
      RECT 0.048 4.992 11.732 5.088 ;
      RECT 0.048 5.760 11.732 5.856 ;
      RECT 0.048 6.528 11.732 6.624 ;
      RECT 0.048 7.296 11.732 7.392 ;
      RECT 0.048 8.064 11.732 8.160 ;
      RECT 0.048 8.832 11.732 8.928 ;
      RECT 0.048 9.600 11.732 9.696 ;
      RECT 0.048 10.368 11.732 10.464 ;
      RECT 0.048 11.136 11.732 11.232 ;
      RECT 0.048 11.904 11.732 12.000 ;
      RECT 0.048 12.672 11.732 12.768 ;
      RECT 0.048 13.440 11.732 13.536 ;
      RECT 0.048 14.208 11.732 14.304 ;
      RECT 0.048 14.976 11.732 15.072 ;
      RECT 0.048 15.744 11.732 15.840 ;
      RECT 0.048 16.512 11.732 16.608 ;
      RECT 0.048 17.280 11.732 17.376 ;
      RECT 0.048 18.048 11.732 18.144 ;
      RECT 0.048 18.816 11.732 18.912 ;
      RECT 0.048 19.584 11.732 19.680 ;
      RECT 0.048 20.352 11.732 20.448 ;
    END
  END VDD
  OBS
    LAYER M1 ;
    RECT 0 0 11.780 21.000 ;
    LAYER M2 ;
    RECT 0 0 11.780 21.000 ;
    LAYER M3 ;
    RECT 0 0 11.780 21.000 ;
    LAYER M4 ;
    RECT 0 0 11.780 21.000 ;
  END
END fakeram7_dp_128x32

END LIBRARY
